VERSION 5.8 ;
BUSBITCHARS "<>" ;
DIVIDERCHAR "/" ;

UNITS
   DATABASE MICRONS 1000 ;
END UNITS

LAYER M1
   TYPE ROUTING ;
   WIDTH 1 ;
   PITCH 2 ;
   DIRECTION HORIZONTAL ;
END M1

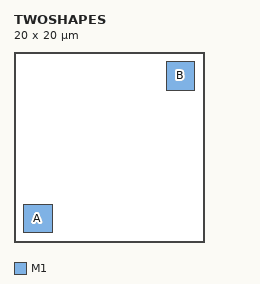
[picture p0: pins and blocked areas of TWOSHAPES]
MACRO TWOSHAPES
   CLASS CORE ;
   SIZE 20 BY 20 ;

   PIN A
      DIRECTION INPUT ;
      PORT
         LAYER M1 ;
         RECT 1 1 4 4 ;
      END
   END A

   PIN B
      DIRECTION OUTPUT ;
      PORT
         LAYER M1 ;
         RECT 16 16 19 19 ;
      END
   END B
END TWOSHAPES
